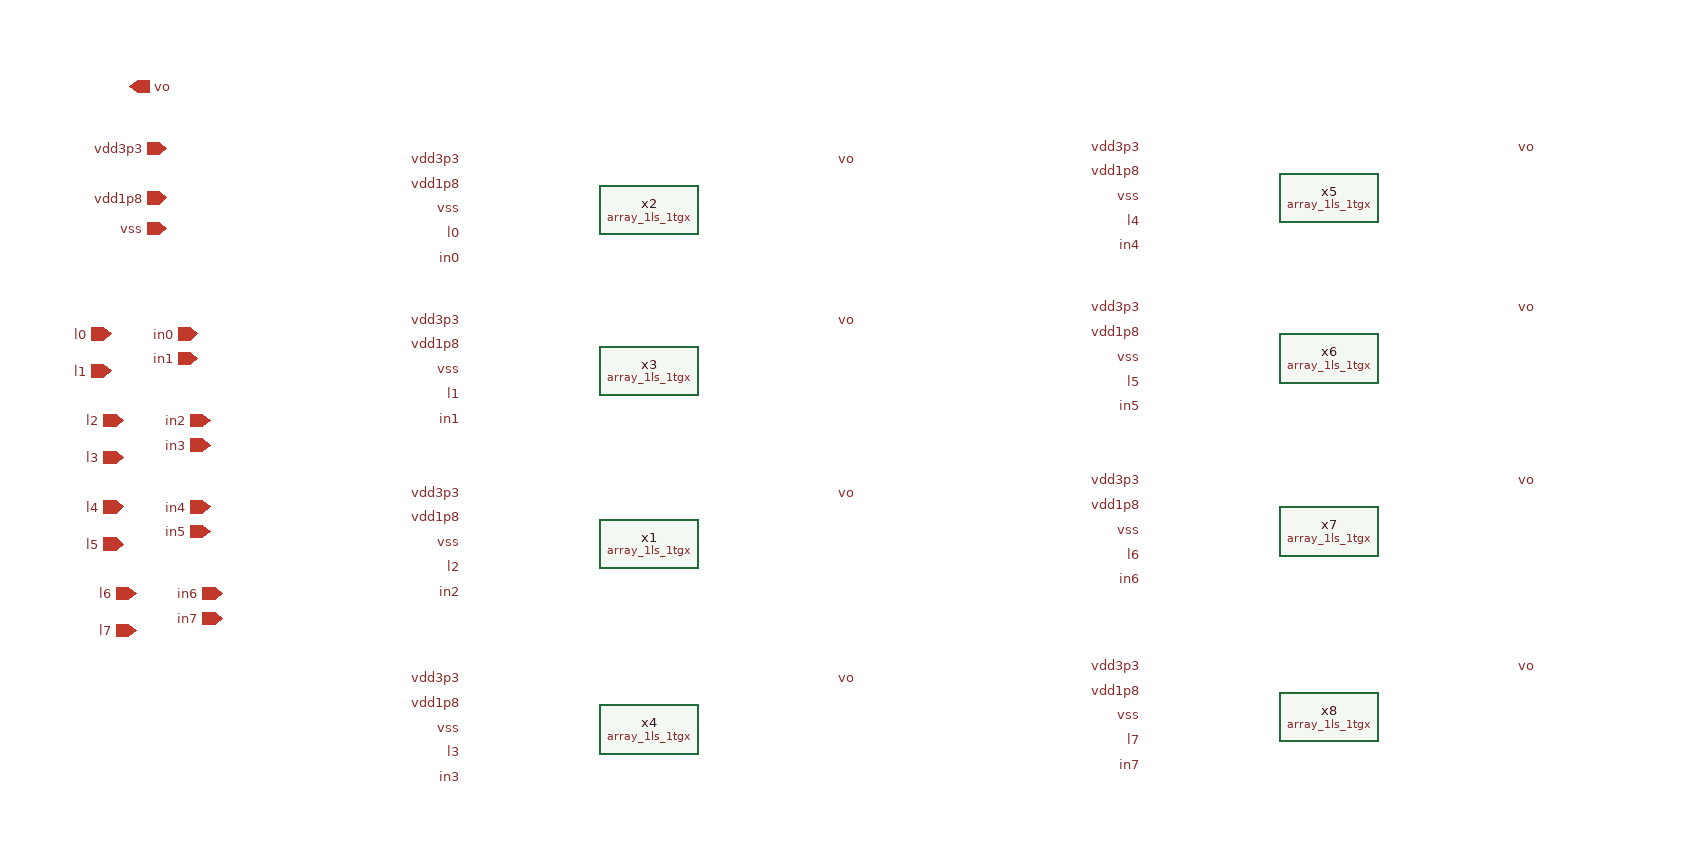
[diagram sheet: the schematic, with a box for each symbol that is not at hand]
v {xschem version=3.1.0 file_version=1.2
}
G {}
K {}
V {}
S {}
E {}
C {devices/ipin.sym} 1350 -1710 0 0 {name=p5 lab=vdd1p8}
C {devices/ipin.sym} 1350 -1750 0 0 {name=p6 lab=vdd3p3}
C {devices/ipin.sym} 1350 -1685 0 0 {name=p4 lab=vss}
C {devices/ipin.sym} 1305 -1600 0 0 {name=p20 lab=l0}
C {devices/opin.sym} 1320 -1800 0 0 {name=p28 lab=vo}
C {devices/ipin.sym} 1375 -1600 0 0 {name=p10 lab=in0}
C {Project/Package_IP/package_EF_ADCS1008NC/EF_ADCS1008NC/spice/xschem/array_1ls_1tgx.sym} 1740 -1700 0 0 {name=x2}
C {Project/Package_IP/package_EF_ADCS1008NC/EF_ADCS1008NC/spice/xschem/array_1ls_1tgx.sym} 1740 -1570 0 0 {name=x3}
C {devices/lab_pin.sym} 1590 -1740 0 0 {name=p13 sig_type=std_logic lab=vdd3p3}
C {devices/lab_pin.sym} 1590 -1610 0 0 {name=p16 sig_type=std_logic lab=vdd3p3}
C {devices/lab_pin.sym} 1590 -1720 0 0 {name=p17 sig_type=std_logic lab=vdd1p8}
C {devices/lab_pin.sym} 1590 -1590 0 0 {name=p18 sig_type=std_logic lab=vdd1p8}
C {devices/lab_pin.sym} 1590 -1570 0 0 {name=p19 sig_type=std_logic lab=vss}
C {devices/lab_pin.sym} 1590 -1700 0 0 {name=p21 sig_type=std_logic lab=vss}
C {devices/lab_pin.sym} 1590 -1680 0 0 {name=p22 sig_type=std_logic lab=l0}
C {devices/lab_pin.sym} 1590 -1550 0 0 {name=p23 sig_type=std_logic lab=l1}
C {devices/lab_pin.sym} 1590 -1660 0 0 {name=p24 sig_type=std_logic lab=in0}
C {devices/lab_pin.sym} 1590 -1530 0 0 {name=p25 sig_type=std_logic lab=in1}
C {devices/lab_pin.sym} 1890 -1740 0 1 {name=p26 sig_type=std_logic lab=vo}
C {devices/lab_pin.sym} 1890 -1610 0 1 {name=p27 sig_type=std_logic lab=vo}
C {devices/ipin.sym} 1305 -1570 0 0 {name=p29 lab=l1}
C {devices/ipin.sym} 1375 -1580 0 0 {name=p30 lab=in1}
C {Project/Package_IP/package_EF_ADCS1008NC/EF_ADCS1008NC/spice/xschem/array_1ls_1tgx.sym} 1740 -1430 0 0 {name=x1}
C {devices/lab_pin.sym} 1590 -1470 0 0 {name=p1 sig_type=std_logic lab=vdd3p3}
C {devices/lab_pin.sym} 1590 -1450 0 0 {name=p2 sig_type=std_logic lab=vdd1p8}
C {devices/lab_pin.sym} 1590 -1430 0 0 {name=p3 sig_type=std_logic lab=vss}
C {devices/lab_pin.sym} 1590 -1410 0 0 {name=p7 sig_type=std_logic lab=l2}
C {devices/lab_pin.sym} 1590 -1390 0 0 {name=p8 sig_type=std_logic lab=in2}
C {devices/lab_pin.sym} 1890 -1470 0 1 {name=p9 sig_type=std_logic lab=vo}
C {Project/Package_IP/package_EF_ADCS1008NC/EF_ADCS1008NC/spice/xschem/array_1ls_1tgx.sym} 1740 -1280 0 0 {name=x4}
C {devices/lab_pin.sym} 1590 -1320 0 0 {name=p11 sig_type=std_logic lab=vdd3p3}
C {devices/lab_pin.sym} 1590 -1300 0 0 {name=p12 sig_type=std_logic lab=vdd1p8}
C {devices/lab_pin.sym} 1590 -1280 0 0 {name=p14 sig_type=std_logic lab=vss}
C {devices/lab_pin.sym} 1590 -1260 0 0 {name=p15 sig_type=std_logic lab=l3}
C {devices/lab_pin.sym} 1590 -1240 0 0 {name=p31 sig_type=std_logic lab=in3}
C {devices/lab_pin.sym} 1890 -1320 0 1 {name=p32 sig_type=std_logic lab=vo}
C {Project/Package_IP/package_EF_ADCS1008NC/EF_ADCS1008NC/spice/xschem/array_1ls_1tgx.sym} 2290 -1710 0 0 {name=x5}
C {Project/Package_IP/package_EF_ADCS1008NC/EF_ADCS1008NC/spice/xschem/array_1ls_1tgx.sym} 2290 -1580 0 0 {name=x6}
C {devices/lab_pin.sym} 2140 -1750 0 0 {name=p33 sig_type=std_logic lab=vdd3p3}
C {devices/lab_pin.sym} 2140 -1620 0 0 {name=p34 sig_type=std_logic lab=vdd3p3}
C {devices/lab_pin.sym} 2140 -1730 0 0 {name=p35 sig_type=std_logic lab=vdd1p8}
C {devices/lab_pin.sym} 2140 -1600 0 0 {name=p36 sig_type=std_logic lab=vdd1p8}
C {devices/lab_pin.sym} 2140 -1580 0 0 {name=p37 sig_type=std_logic lab=vss}
C {devices/lab_pin.sym} 2140 -1710 0 0 {name=p38 sig_type=std_logic lab=vss}
C {devices/lab_pin.sym} 2140 -1690 0 0 {name=p39 sig_type=std_logic lab=l4}
C {devices/lab_pin.sym} 2140 -1560 0 0 {name=p40 sig_type=std_logic lab=l5}
C {devices/lab_pin.sym} 2140 -1670 0 0 {name=p41 sig_type=std_logic lab=in4}
C {devices/lab_pin.sym} 2140 -1540 0 0 {name=p42 sig_type=std_logic lab=in5}
C {devices/lab_pin.sym} 2440 -1750 0 1 {name=p43 sig_type=std_logic lab=vo}
C {devices/lab_pin.sym} 2440 -1620 0 1 {name=p44 sig_type=std_logic lab=vo}
C {Project/Package_IP/package_EF_ADCS1008NC/EF_ADCS1008NC/spice/xschem/array_1ls_1tgx.sym} 2290 -1440 0 0 {name=x7}
C {devices/lab_pin.sym} 2140 -1480 0 0 {name=p45 sig_type=std_logic lab=vdd3p3}
C {devices/lab_pin.sym} 2140 -1460 0 0 {name=p46 sig_type=std_logic lab=vdd1p8}
C {devices/lab_pin.sym} 2140 -1440 0 0 {name=p47 sig_type=std_logic lab=vss}
C {devices/lab_pin.sym} 2140 -1420 0 0 {name=p48 sig_type=std_logic lab=l6}
C {devices/lab_pin.sym} 2140 -1400 0 0 {name=p49 sig_type=std_logic lab=in6}
C {devices/lab_pin.sym} 2440 -1480 0 1 {name=p50 sig_type=std_logic lab=vo}
C {Project/Package_IP/package_EF_ADCS1008NC/EF_ADCS1008NC/spice/xschem/array_1ls_1tgx.sym} 2290 -1290 0 0 {name=x8}
C {devices/lab_pin.sym} 2140 -1330 0 0 {name=p51 sig_type=std_logic lab=vdd3p3}
C {devices/lab_pin.sym} 2140 -1310 0 0 {name=p52 sig_type=std_logic lab=vdd1p8}
C {devices/lab_pin.sym} 2140 -1290 0 0 {name=p53 sig_type=std_logic lab=vss}
C {devices/lab_pin.sym} 2140 -1270 0 0 {name=p54 sig_type=std_logic lab=l7}
C {devices/lab_pin.sym} 2140 -1250 0 0 {name=p55 sig_type=std_logic lab=in7}
C {devices/lab_pin.sym} 2440 -1330 0 1 {name=p56 sig_type=std_logic lab=vo}
C {devices/ipin.sym} 1315 -1530 0 0 {name=p57 lab=l2}
C {devices/ipin.sym} 1385 -1530 0 0 {name=p58 lab=in2}
C {devices/ipin.sym} 1315 -1500 0 0 {name=p59 lab=l3}
C {devices/ipin.sym} 1385 -1510 0 0 {name=p60 lab=in3}
C {devices/ipin.sym} 1315 -1460 0 0 {name=p61 lab=l4}
C {devices/ipin.sym} 1385 -1460 0 0 {name=p62 lab=in4}
C {devices/ipin.sym} 1315 -1430 0 0 {name=p63 lab=l5}
C {devices/ipin.sym} 1385 -1440 0 0 {name=p64 lab=in5}
C {devices/ipin.sym} 1325 -1390 0 0 {name=p65 lab=l6}
C {devices/ipin.sym} 1395 -1390 0 0 {name=p66 lab=in6}
C {devices/ipin.sym} 1325 -1360 0 0 {name=p67 lab=l7}
C {devices/ipin.sym} 1395 -1370 0 0 {name=p68 lab=in7}
